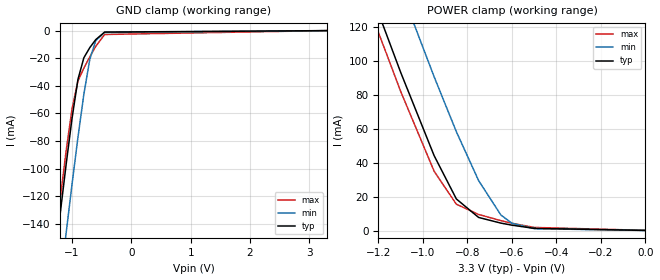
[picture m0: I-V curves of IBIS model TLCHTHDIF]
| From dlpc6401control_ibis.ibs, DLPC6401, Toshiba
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[Model]   TLCHTHDIF
Model_type   Input
Polarity   Non-Inverting
Vinl =   0.8000V
Vinh =   2.0000V
C_comp   1.423pF   NA   NA
|Variable   typ   min   max
[Voltage range]  3.3   3.0   3.6
[Temperature Range]   25.0000   125.000   0.000
[POWER Clamp Reference]   3.3000V   3.0000V   3.6000V
[GND Clamp Reference]   0.000V   0.000V   0.000V
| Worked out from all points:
|   GND clamp passes 1 mA (typ) near -0.45 V on its own axis
|   POWER clamp passes 1 mA (typ) near -0.48 V on its own axis
[GND_clamp]
| voltage   I(typ)   I(min)   I(max)
-3.3V     -944.9mA   -993.5mA   -933.7mA
-1.3V     -169.6mA   -220.5mA   -158.5mA
-1.25V    -151.2mA   -201.9mA   -140.2mA
-1.2V     -132.9mA   -183.4mA   -122.2mA
-1.1V     -97.21mA   -147mA     -87.48mA
-1V       -63.64mA   -111.4mA   -56.63mA
-900mV    -35.31mA   -77.26mA   -36.42mA
-800mV    -19.56mA   -45.93mA   -27.09mA
-700mV    -12.24mA   -20.73mA   -18.9mA
-600mV    -6.457mA   -7.167mA   -11.32mA
-450mV    -981uA     -1.198mA   -2.726mA
3.3V      72.06uA    62.27uA    111.7uA
[POWER_clamp]
| voltage   I(typ)   I(min)   I(max)
-3.3V     917.5mA    964.8mA    906.4mA
-1.3V     164.1mA    213.9mA    152.5mA
-1.25V    146.1mA    195.8mA    134.5mA
-1.2V     128.2mA    177.9mA    116.7mA
-1.1V     93.15mA    142.3mA    81.93mA
-950mV    44.17mA    90.68mA    34.98mA
-850mV    18.62mA    58.27mA    15.52mA
-750mV    7.719mA    29.47mA    9.484mA
-650mV    4.383mA    9.19mA     5.848mA
-600mV    3.161mA    4.286mA    4.295mA
-500mV    1.278mA    1.099mA    1.824mA
0V        72.06uA    38.01uA    111.9uA
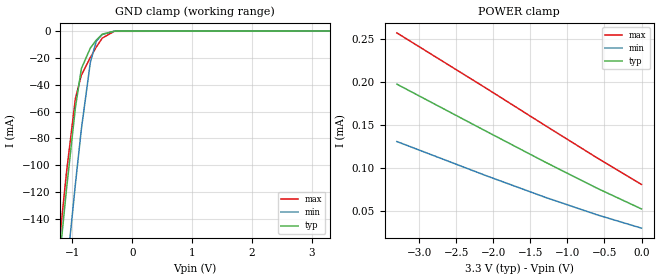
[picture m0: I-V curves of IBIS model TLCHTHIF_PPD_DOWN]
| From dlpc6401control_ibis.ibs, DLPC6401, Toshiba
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[Model]   TLCHTHIF_PPD_DOWN
Model_type   Input
Polarity   Non-Inverting
Vinl =   0.8000V
Vinh =   2.0000V
C_comp   1.423pF   NA   NA
|Variable   typ   min   max
[Voltage range]  3.3   3.0   3.6
[Temperature Range]   25.0000   125.000   0.000
[POWER Clamp Reference]   3.3000V   3.0000V   3.6000V
[GND Clamp Reference]   0.000V   0.000V   0.000V
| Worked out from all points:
|   GND clamp passes 1 mA (typ) near -0.45 V on its own axis
[GND_clamp]
| voltage   I(typ)   I(min)   I(max)
-3.3V     -1.18A     -1.24A     -1.166A
-1.3V     -209.3mA   -272.2mA   -195.2mA
-1.25V    -186.1mA   -249mA     -172.2mA
-1.2V     -163.2mA   -225.9mA   -149.6mA
-1.1V     -118.5mA   -180.3mA   -105.8mA
-950mV    -57.04mA   -114.1mA   -50.29mA
-850mV    -27.88mA   -73mA      -32.78mA
-700mV    -12.61mA   -23.19mA   -19.66mA
-600mV    -6.597mA   -7.45mA    -11.71mA
-500mV    -2.24mA    -2.388mA   -5.154mA
-300mV    -17.81uA   -59.37uA   -84.02uA
3.3V      52.45uA    37.67uA    66.26uA
[POWER_clamp]
| voltage   I(typ)   I(min)   I(max)
-3.3V     197.1uA    130.6uA    256.5uA
-2.1V     142.7uA    91.15uA    192.6uA
-1.3V     106.8uA    66uA       149.2uA
-600mV    76.5uA     45.68uA    111.7uA
0V        52.46uA    30.2uA     80.84uA
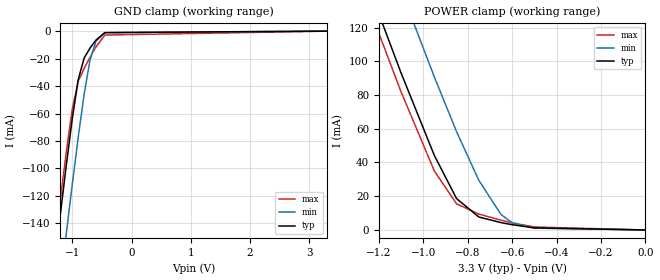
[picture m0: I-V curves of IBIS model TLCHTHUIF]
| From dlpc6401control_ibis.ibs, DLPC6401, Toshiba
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[Model]   TLCHTHUIF
Model_type   Input
Polarity   Non-Inverting
Vinl =   0.8000V
Vinh =   2.0000V
C_comp   1.423pF   NA   NA
|Variable   typ   min   max
[Voltage range]  3.3   3.0   3.6
[Temperature Range]   25.0000   125.000   0.000
[POWER Clamp Reference]   3.3000V   3.0000V   3.6000V
[GND Clamp Reference]   0.000V   0.000V   0.000V
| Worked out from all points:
|   GND clamp passes 1 mA (typ) near -0.45 V on its own axis
|   POWER clamp passes 1 mA (typ) near -0.48 V on its own axis
[GND_clamp]
| voltage   I(typ)   I(min)   I(max)
-3.3V     -944.9mA   -993.5mA   -933.7mA
-1.3V     -169.6mA   -220.5mA   -158.5mA
-1.25V    -151.2mA   -201.9mA   -140.2mA
-1.2V     -132.9mA   -183.4mA   -122.2mA
-1.1V     -97.22mA   -147mA     -87.49mA
-1V       -63.65mA   -111.4mA   -56.65mA
-900mV    -35.33mA   -77.27mA   -36.46mA
-800mV    -19.6mA    -45.94mA   -27.16mA
-700mV    -12.28mA   -20.75mA   -18.98mA
-600mV    -6.507mA   -7.188mA   -11.4mA
-450mV    -1.04mA    -1.222mA   -2.82mA
3.3V      2.124nA    35.56uA    -25.2uA
[POWER_clamp]
| voltage   I(typ)   I(min)   I(max)
-3.3V     917.5mA    964.8mA    906.4mA
-1.3V     164.1mA    213.9mA    152.5mA
-1.25V    146.1mA    195.8mA    134.5mA
-1.2V     128.2mA    177.9mA    116.7mA
-1.1V     93.14mA    142.3mA    81.93mA
-950mV    44.16mA    90.68mA    34.97mA
-850mV    18.6mA     58.27mA    15.49mA
-750mV    7.699mA    29.46mA    9.443mA
-650mV    4.358mA    9.175mA    5.797mA
-600mV    3.132mA    4.268mA    4.24mA
-500mV    1.241mA    1.079mA    1.758mA
0V        2.123nA    56.31nA    15.39nA
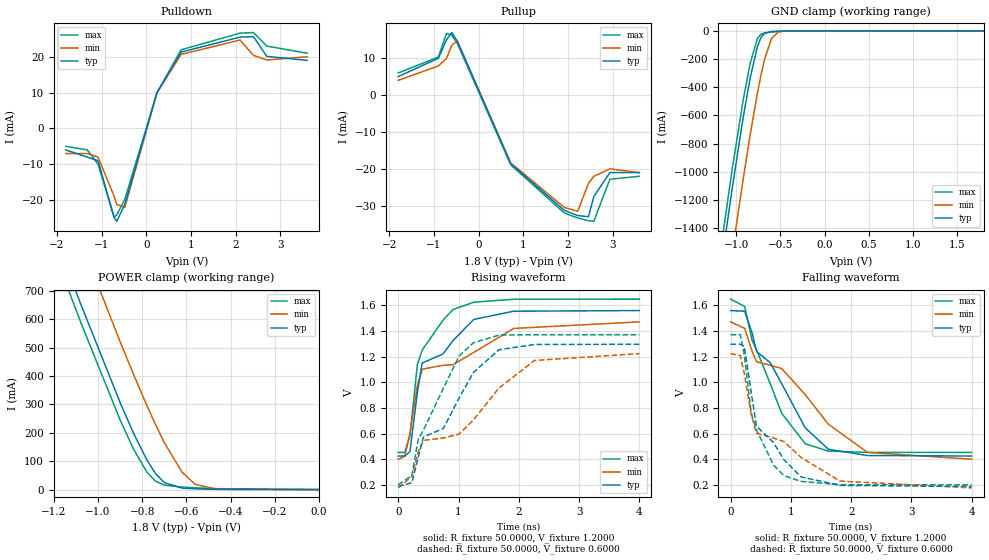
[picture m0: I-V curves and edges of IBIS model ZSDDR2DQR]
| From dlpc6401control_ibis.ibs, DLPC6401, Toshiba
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[Model]  ZSDDR2DQR
Model_type I/O
Polarity   Non-Inverting
Vinl =   0.7000V
Vinh =   1.1000V
Vmeas =  0.9000V
C_comp 6.694e-13 6.602e-13 6.945e-13
[Temperature Range]   25.0000   0.1050k   0.0
[Voltage Range]   1.8000V   1.7000V   1.9000V
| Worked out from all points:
|   slope of the pulldown table from 0 to 0.27 V, typ, clamps not added: 24.5 ohm
|   slope of the pullup table from 0 to 0.27 V, typ, clamps not added: 34 ohm
|   GND clamp passes 1 mA (typ) near -0.47 V on its own axis
|   POWER clamp passes 1 mA (typ) near -0.48 V on its own axis
|   rising waveform, R_fixture 50.0000, V_fixture 1.2000: 20-80 % time 663ps typ, 1.11ns min, 436ps max; typ from 0.426 V to 1.56 V
|   rising waveform, R_fixture 50.0000, V_fixture 0.6000: 20-80 % time 914ps typ, 1.49ns min, 634ps max; typ from 0.189 V to 1.3 V
|   falling waveform, R_fixture 50.0000, V_fixture 1.2000: 20-80 % time 849ps typ, 1.39ns min, 596ps max; typ from 1.56 V to 0.426 V
|   falling waveform, R_fixture 50.0000, V_fixture 0.6000: 20-80 % time 566ps typ, 976ps min, 380ps max; typ from 1.3 V to 0.189 V
[Pulldown]
|Voltage   I(typ)   I(min)   I(max)
-1.8V     -6mA       -7mA       -5mA
-1.32V    -8mA       -7mA       -6mA
-1.08V    -9mA       -8mA       -10mA
-720mV    -24.87mA   -18.9mA    -24.74mA
-660mV    -25.91mA   -21.2mA    -24.11mA
-480mV    -21.17mA   -22.03mA   -19.76mA
240mV     10.03mA    9.948mA    9.967mA
780mV     21.3mA     20.66mA    21.93mA
2.1V      25.48mA    24.67mA    26.59mA
2.4V      25.6mA     20.4mA     26.75mA
2.7V      20.1mA     19.1mA     22.98mA
3.6V      19mA       20mA       21mA
[Pullup]
|Voltage   I(typ)   I(min)   I(max)
-1.8V     5mA        4mA        6mA
-900mV    10mA       7.9mA      10.3mA
-720mV    14.97mA    9.9mA      16.72mA
-600mV    16.94mA    13.48mA    16.19mA
-480mV    14.67mA    14.72mA    14.09mA
720mV     -18.61mA   -18.39mA   -18.9mA
1.92V     -31.25mA   -30.44mA   -31.94mA
2.22V     -32.64mA   -31.48mA   -33.31mA
2.46V     -32.95mA   -23.9mA    -34.03mA
2.58V     -27.5mA    -22mA      -34.2mA
2.94V     -21mA      -20mA      -22.8mA
3.6V      -21mA      -21mA      -22mA
[GND_clamp]
|Voltage   I(typ)   I(min)   I(max)
-1.8V     -4.552A    -5A        -4.417A
-1.2V     -1.796A    -2.258A    -1.657A
-1.04V    -1.096A    -1.554A    -960.9mA
-920mV    -610.6mA   -1.048A    -487.7mA
-840mV    -329.1mA   -730.5mA   -226mA
-760mV    -112.6mA   -442.5mA   -55.33mA
-720mV    -47.89mA   -315.5mA   -24.39mA
-680mV    -17.9mA    -204.5mA   -14.69mA
-600mV    -4.679mA   -53.33mA   -8.766mA
-520mV    -1.893mA   -6.808mA   -5.004mA
-440mV    -538.1uA   -693.5uA   -2.133mA
1.8V      2.102uA    2.14uA     2.104uA
[POWER_clamp]
|Voltage   I(typ)   I(min)   I(max)
-1.8V     2.171A     2.383A     2.113A
-1.34V    1.193A     1.413A     1.13A
-1.08V    656.8mA    877.4mA    592.2mA
-900mV    306.1mA    520.5mA    245.1mA
-840mV    199.6mA    406.8mA    143.6mA
-780mV    105.8mA    297.8mA    62.49mA
-740mV    56.54mA    229.1mA    29.73mA
-700mV    24.56mA    165.1mA    15.68mA
-620mV    5.27mA     61.39mA    8.716mA
-560mV    2.752mA    18.33mA    6.27mA
-460mV    768.4uA    1.282mA    2.862mA
0V        2.102uA    1.987uA    2.233uA
[Ramp]
| variable   typ   min   max
dV/dt_r  0.6018/0.6192n   0.5693/0.8711n   0.6354/0.5158n
dV/dt_f  0.6299/0.6935n   0.5975/0.9821n   0.6629/0.5809n
R_load = 50.0000
|VT clipping
|1 DELAY=0.0
|2 DELAY=1.7e-10
|3 DELAY=0.0
[Rising Waveform]
R_fixture= 50.0000
V_fixture= 1.2000
V_fixture_min= 1.1333
V_fixture_max= 1.2667
|time   V(typ)   V(min)   V(max)
0s        426.3mV    401.2mV    454.6mV
109ps     426.2mV    422.8mV    454.6mV
194ps     459.9mV    605.6mV    581.5mV
318ps     921.4mV    977.2mV    1.139V
398ps     1.15V      1.102V     1.251V
741ps     1.22V      1.132V     1.482V
909ps     1.325V     1.137V     1.566V
1.252ns   1.489V     1.232V     1.623V
1.915ns   1.553V     1.419V     1.646V
3.999ns   1.558V     1.47V      1.647V
[Rising Waveform]
R_fixture= 50.0000
V_fixture= 0.6000
V_fixture_min= 0.5667
V_fixture_max= 0.6333
|time   V(typ)   V(min)   V(max)
0s        189.3mV    178.7mV    202.3mV
227ps     218.4mV    268.5mV    275.2mV
332ps     415.7mV    459.1mV    556.9mV
417ps     573.4mV    548mV      626.5mV
750ps     642.3mV    566.3mV    954.2mV
1.01ns    877.8mV    597.1mV    1.205V
1.248ns   1.077V     706.7mV    1.308V
1.67ns    1.253V     955mV      1.367V
2.26ns    1.294V     1.17V      1.37V
3.999ns   1.296V     1.223V     1.37V
[Falling Waveform]
R_fixture= 50.0000
V_fixture= 1.2000
V_fixture_min= 1.1333
V_fixture_max= 1.2667
|time   V(typ)   V(min)   V(max)
0s        1.558V     1.47V      1.647V
235ps     1.553V     1.419V     1.59V
357ps     1.384V     1.243V     1.327V
431ps     1.241V     1.16V      1.252V
659ps     1.152V     1.133V     988.3mV
848ps     989.3mV    1.107V     759.2mV
1.237ns   646.7mV    905mV      522.3mV
1.623ns   479mV      673.5mV    464.6mV
2.271ns   430.6mV    454.8mV    455.1mV
3.999ns   426.3mV    401.8mV    454.6mV
[Falling Waveform]
R_fixture= 50.0000
V_fixture= 0.6000
V_fixture_min= 0.5667
V_fixture_max= 0.6333
|time   V(typ)   V(min)   V(max)
0s        1.296V     1.223V     1.37V
160ps     1.297V     1.208V     1.371V
227ps     1.281V     1.073V     1.218V
342ps     924.9mV    750.9mV    761.3mV
429ps     659.6mV    604.1mV    630.9mV
715ps     530.1mV    566mV      354.5mV
885ps     397.6mV    539.5mV    273.8mV
1.171ns   263.7mV    414.9mV    229.1mV
1.815ns   197.8mV    231.6mV    203.7mV
3.999ns   189.3mV    178.9mV    202.3mV
